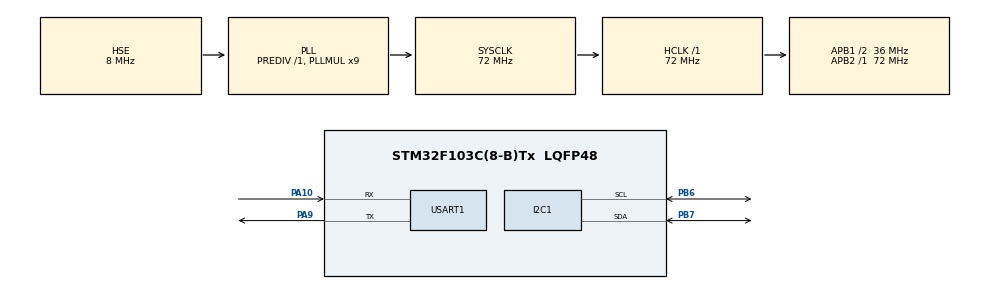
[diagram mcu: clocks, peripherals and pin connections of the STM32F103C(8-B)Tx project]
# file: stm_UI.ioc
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FREERTOS.Tasks01=defaultTask,0,128,StartDefaultTask,Default,NULL,Dynamic,NULL,NULL
I2C1.I2C_Mode=I2C_Fast
Mcu.Family=STM32F1
Mcu.Name=STM32F103C(8-B)Tx
Mcu.Package=LQFP48
NVIC.PriorityGroup=NVIC_PRIORITYGROUP_4
NVIC.TIM1_UP_IRQn=true\:15\:0\:false\:false\:true\:false\:false\:true\:true
NVIC.TimeBase=TIM1_UP_IRQn
NVIC.TimeBaseIP=TIM1
PA10.Mode=Asynchronous
PA10.Signal=USART1_RX
PA13.Mode=Serial_Wire
PA13.Signal=SYS_JTMS-SWDIO
PA14.Mode=Serial_Wire
PA14.Signal=SYS_JTCK-SWCLK
PA9.Mode=Asynchronous
PA9.Signal=USART1_TX
PB6.Mode=I2C
PB6.Signal=I2C1_SCL
PB7.Mode=I2C
PB7.Signal=I2C1_SDA
PD0-OSC_IN.Mode=HSE-External-Oscillator
PD0-OSC_IN.Signal=RCC_OSC_IN
PD1-OSC_OUT.Mode=HSE-External-Oscillator
PD1-OSC_OUT.Signal=RCC_OSC_OUT
ProjectManager.HeapSize=0x200
ProjectManager.StackSize=0x400
ProjectManager.TargetToolchain=Makefile
RCC.AHBFreq_Value=72000000
RCC.APB1CLKDivider=RCC_HCLK_DIV2
RCC.APB1Freq_Value=36000000
RCC.APB1TimFreq_Value=72000000
RCC.APB2Freq_Value=72000000
RCC.APB2TimFreq_Value=72000000
RCC.HCLKFreq_Value=72000000
RCC.PLLMUL=RCC_PLL_MUL9
RCC.PLLSourceVirtual=RCC_PLLSOURCE_HSE
RCC.SYSCLKFreq_VALUE=72000000
RCC.SYSCLKSource=RCC_SYSCLKSOURCE_PLLCLK
RCC.USBFreq_Value=72000000
USART1.VirtualMode=VM_ASYNC
VP_FREERTOS_VS_CMSIS_V1.Mode=CMSIS_V1
VP_SYS_VS_tim1.Mode=TIM1
board=custom

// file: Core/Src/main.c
/* USER CODE BEGIN Header */
/**
 ******************************************************************************
 * @file           : main.c
 * @brief          : Main program body
 ******************************************************************************
 * @attention
 *
 * Copyright (c) 2025 STMicroelectronics.
 * All rights reserved.
 *
 * This software is licensed under terms that can be found in the LICENSE file
 * in the root directory of this software component.
 * If no LICENSE file comes with this software, it is provided AS-IS.
 *
 ******************************************************************************
 */
/* USER CODE END Header */
#include "main.h"
#include "cmsis_os.h"
#include "vram.h"

/* USER CODE BEGIN Includes */
#include "task.h"
#include "FreeRTOS.h"
#include "driver_oled.h"
#include "ui.h"
#include "task.h"
/* USER CODE END Includes */

I2C_HandleTypeDef hi2c1;

UART_HandleTypeDef huart1;

osThreadId defaultTaskHandle;

void SystemClock_Config(void);
static void MX_GPIO_Init(void);
static void MX_I2C1_Init(void);
static void MX_USART1_UART_Init(void);
void StartDefaultTask(void *argument);

int main(void)
{

  /* MCU Configuration--------------------------------------------------------*/

  /* Reset of all peripherals, Initializes the Flash interface and the Systick. */
  HAL_Init();

  /* Configure the system clock */
  SystemClock_Config();

  /* Initialize all configured peripherals */
  MX_GPIO_Init();
  MX_I2C1_Init();
  MX_USART1_UART_Init();
  /* USER CODE BEGIN 2 */
  OLED_Init();
  OLED_Clear();
  // send_vram_data_to_oled_test();
  /* USER CODE END 2 */

  /* Create the thread(s) */
  /* definition and creation of defaultTask */
  // osThreadDef(defaultTask, StartDefaultTask, osPriorityNormal, 0, 2056);
  // defaultTaskHandle = osThreadCreate(osThread(defaultTask), NULL);
  // StackType_t StackofLcdTask[128 * 4];
  // StaticTask_t TCBofLcdTask;
  xTaskCreate(StartDefaultTask, NULL, 128*10, NULL, osPriorityNormal, NULL);

  /* Start scheduler */
  osKernelStart();

  /* We should never get here as control is now taken by the scheduler */
  /* Infinite loop */
  while (1)
  {

  }
}

void SystemClock_Config(void)
{
  RCC_OscInitTypeDef RCC_OscInitStruct = {0};
  RCC_ClkInitTypeDef RCC_ClkInitStruct = {0};

  /** Initializes the RCC Oscillators according to the specified parameters
   * in the RCC_OscInitTypeDef structure.
   */
  RCC_OscInitStruct.OscillatorType = RCC_OSCILLATORTYPE_HSE;
  RCC_OscInitStruct.HSEState = RCC_HSE_ON;
  RCC_OscInitStruct.HSEPredivValue = RCC_HSE_PREDIV_DIV1;
  RCC_OscInitStruct.HSIState = RCC_HSI_ON;
  RCC_OscInitStruct.PLL.PLLState = RCC_PLL_ON;
  RCC_OscInitStruct.PLL.PLLSource = RCC_PLLSOURCE_HSE;
  RCC_OscInitStruct.PLL.PLLMUL = RCC_PLL_MUL9;
  if (HAL_RCC_OscConfig(&RCC_OscInitStruct) != HAL_OK)
  {
    Error_Handler();
  }

  /** Initializes the CPU, AHB and APB buses clocks
   */
  RCC_ClkInitStruct.ClockType = RCC_CLOCKTYPE_HCLK | RCC_CLOCKTYPE_SYSCLK | RCC_CLOCKTYPE_PCLK1 | RCC_CLOCKTYPE_PCLK2;
  RCC_ClkInitStruct.SYSCLKSource = RCC_SYSCLKSOURCE_PLLCLK;
  RCC_ClkInitStruct.AHBCLKDivider = RCC_SYSCLK_DIV1;
  RCC_ClkInitStruct.APB1CLKDivider = RCC_HCLK_DIV2;
  RCC_ClkInitStruct.APB2CLKDivider = RCC_HCLK_DIV1;

  if (HAL_RCC_ClockConfig(&RCC_ClkInitStruct, FLASH_LATENCY_2) != HAL_OK)
  {
    Error_Handler();
  }
}

static void MX_I2C1_Init(void)
{

  hi2c1.Instance = I2C1;
  hi2c1.Init.ClockSpeed = 400000;
  hi2c1.Init.DutyCycle = I2C_DUTYCYCLE_2;
  hi2c1.Init.OwnAddress1 = 0;
  hi2c1.Init.AddressingMode = I2C_ADDRESSINGMODE_7BIT;
  hi2c1.Init.DualAddressMode = I2C_DUALADDRESS_DISABLE;
  hi2c1.Init.OwnAddress2 = 0;
  hi2c1.Init.GeneralCallMode = I2C_GENERALCALL_DISABLE;
  hi2c1.Init.NoStretchMode = I2C_NOSTRETCH_DISABLE;
  if (HAL_I2C_Init(&hi2c1) != HAL_OK)
  {
    Error_Handler();
  }
}

static void MX_USART1_UART_Init(void)
{

  huart1.Instance = USART1;
  huart1.Init.BaudRate = 115200;
  huart1.Init.WordLength = UART_WORDLENGTH_8B;
  huart1.Init.StopBits = UART_STOPBITS_1;
  huart1.Init.Parity = UART_PARITY_NONE;
  huart1.Init.Mode = UART_MODE_TX_RX;
  huart1.Init.HwFlowCtl = UART_HWCONTROL_NONE;
  huart1.Init.OverSampling = UART_OVERSAMPLING_16;
  if (HAL_UART_Init(&huart1) != HAL_OK)
  {
    Error_Handler();
  }
}

static void MX_GPIO_Init(void)
{
  GPIO_InitTypeDef GPIO_InitStruct = {0};

  /* GPIO Ports Clock Enable */
  __HAL_RCC_GPIOD_CLK_ENABLE();
  __HAL_RCC_GPIOB_CLK_ENABLE();
  __HAL_RCC_GPIOA_CLK_ENABLE();

  /*Configure GPIO pin Output Level */
  HAL_GPIO_WritePin(GPIOB, GPIO_PIN_12|GPIO_PIN_13, GPIO_PIN_RESET);

  /*Configure GPIO pins : PB12 PB13 */
  GPIO_InitStruct.Pin = GPIO_PIN_12|GPIO_PIN_13;
  GPIO_InitStruct.Mode = GPIO_MODE_OUTPUT_PP;
  GPIO_InitStruct.Pull = GPIO_NOPULL;
  GPIO_InitStruct.Speed = GPIO_SPEED_FREQ_LOW;
  HAL_GPIO_Init(GPIOB, &GPIO_InitStruct);

  /*Configure GPIO pins : PB14 PB15 */
  GPIO_InitStruct.Pin = GPIO_PIN_14|GPIO_PIN_15;
  GPIO_InitStruct.Mode = GPIO_MODE_INPUT;
  GPIO_InitStruct.Pull = GPIO_PULLUP;
  HAL_GPIO_Init(GPIOB, &GPIO_InitStruct);

}

void StartDefaultTask(void *argument)
{
  /* USER CODE BEGIN 5 */
  /* Infinite loop */
  for (;;)
  {
    // send_vram_data_to_oled_test();
    // OLED_Clear();
    // write_to_vram_test();
    // send_vram_data_to_oled_test();
    // write_to_vram_test();
    // MY_OLED_WriteNBytes(test01_data, 16);
    show_UI();
    // osDelay(1000);
  }
  /* USER CODE END 5 */
}

void HAL_TIM_PeriodElapsedCallback(TIM_HandleTypeDef *htim)
{
  if (htim->Instance == TIM1)
  {
    HAL_IncTick();
  }
}

void Error_Handler(void)
{
  __disable_irq();
  while (1)
  {
  }
}
